VERSION 5.8 ;
BUSBITCHARS "[]" ;
DIVIDERCHAR "/" ;
UNITS
    DATABASE MICRONS 1000 ;
END UNITS

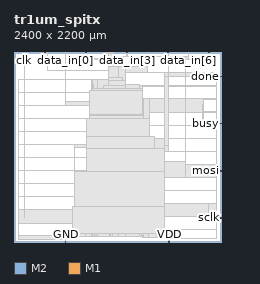
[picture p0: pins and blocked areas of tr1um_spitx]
MACRO tr1um_spitx
  FOREIGN tr1um_spitx 0 0 ;
  CLASS BLOCK ;
  SIZE 2400 BY 2200 ;
  PIN GND
    DIRECTION INOUT ;
    USE SIGNAL ;
    PORT
      LAYER M2 ;
        RECT  593.7 0 599.7 6 ;
    END
  END GND
  PIN VDD
    DIRECTION INOUT ;
    USE SIGNAL ;
    PORT
      LAYER M2 ;
        RECT  1792.5 0 1798.5 6 ;
    END
  END VDD
  PIN busy
    DIRECTION OUTPUT ;
    USE SIGNAL ;
    PORT
      LAYER M1 ;
        RECT  2396.4 1367.1 2400 1370.7 ;
    END
  END busy
  PIN clk
    DIRECTION INPUT ;
    USE SIGNAL ;
    PORT
      LAYER M2 ;
        RECT  118.5 2194 124.5 2200 ;
    END
  END clk
  PIN data_in[0]
    DIRECTION INPUT ;
    USE SIGNAL ;
    PORT
      LAYER M2 ;
        RECT  593.7 2194 599.7 2200 ;
    END
  END data_in[0]
  PIN data_in[1]
    DIRECTION INPUT ;
    USE SIGNAL ;
    PORT
      LAYER M2 ;
        RECT  831.3 2194 837.3 2200 ;
    END
  END data_in[1]
  PIN data_in[2]
    DIRECTION INPUT ;
    USE SIGNAL ;
    PORT
      LAYER M2 ;
        RECT  1068.9 2194 1074.9 2200 ;
    END
  END data_in[2]
  PIN data_in[3]
    DIRECTION INPUT ;
    USE SIGNAL ;
    PORT
      LAYER M2 ;
        RECT  1306.5 2194 1312.5 2200 ;
    END
  END data_in[3]
  PIN data_in[4]
    DIRECTION INPUT ;
    USE SIGNAL ;
    PORT
      LAYER M2 ;
        RECT  1544.1 2194 1550.1 2200 ;
    END
  END data_in[4]
  PIN data_in[5]
    DIRECTION INPUT ;
    USE SIGNAL ;
    PORT
      LAYER M2 ;
        RECT  1781.7 2194 1787.7 2200 ;
    END
  END data_in[5]
  PIN data_in[6]
    DIRECTION INPUT ;
    USE SIGNAL ;
    PORT
      LAYER M2 ;
        RECT  2019.3 2194 2025.3 2200 ;
    END
  END data_in[6]
  PIN data_in[7]
    DIRECTION INPUT ;
    USE SIGNAL ;
    PORT
      LAYER M2 ;
        RECT  2256.9 2194 2262.9 2200 ;
    END
  END data_in[7]
  PIN done
    DIRECTION OUTPUT ;
    USE SIGNAL ;
    PORT
      LAYER M1 ;
        RECT  2396.4 1912.5 2400 1916.1 ;
    END
  END done
  PIN mosi
    DIRECTION OUTPUT ;
    USE SIGNAL ;
    PORT
      LAYER M1 ;
        RECT  2396.4 821.7 2400 825.3 ;
    END
  END mosi
  PIN sclk
    DIRECTION OUTPUT ;
    USE SIGNAL ;
    PORT
      LAYER M1 ;
        RECT  2396.4 276.3 2400 279.9 ;
    END
  END sclk
  PIN start
    DIRECTION INPUT ;
    USE SIGNAL ;
    PORT
      LAYER M2 ;
        RECT  356.1 2194 362.1 2200 ;
    END
  END start
  OBS
    LAYER M1 ;
     RECT  53.1 29.1 54.9 1883.9 ;
     RECT  54.9 29.1 595 69.5 ;
     RECT  54.9 1579.7 595.8 1581.5 ;
     RECT  595 28.3 598.4 69.5 ;
     RECT  598.4 67.7 692.3 69.5 ;
     RECT  54.9 218.9 692.3 371.9 ;
     RECT  54.9 1126.1 703.8 1127.9 ;
     RECT  54.9 521.3 720 523.1 ;
     RECT  54.9 672.5 720 674.3 ;
     RECT  54.9 823.7 784.8 825.5 ;
     RECT  692.3 67.7 832.5 371.9 ;
     RECT  720 521.3 832.5 674.3 ;
     RECT  54.9 1428.5 844.2 1430.3 ;
     RECT  844.2 1422 865.8 1430.3 ;
     RECT  54.9 1277.3 871.2 1279.1 ;
     RECT  703.8 1098 873.8 1127.9 ;
     RECT  871.2 1260 873.8 1279.1 ;
     RECT  784.8 817.2 882 825.5 ;
     RECT  54.9 974.9 882 976.7 ;
     RECT  865.8 1416.6 887.5 1430.3 ;
     RECT  595.8 1579.7 887.5 1623.6 ;
     RECT  882 817.2 890.3 976.7 ;
     RECT  873.8 1098 890.3 1279.1 ;
     RECT  887.5 1416.6 890.3 1623.6 ;
     RECT  832.5 67.7 895.8 674.3 ;
     RECT  890.3 817.2 895.8 1623.6 ;
     RECT  54.9 1730.9 901.3 1732.7 ;
     RECT  54.9 1882.1 901.3 1883.9 ;
     RECT  895.8 67.7 904 1623.6 ;
     RECT  901.3 1730.9 904 1883.9 ;
     RECT  904 67.7 968.4 1883.9 ;
     RECT  833.4 2118.6 1092.6 2120.4 ;
     RECT  1092.6 2118.6 1103.4 2147.4 ;
     RECT  1103.4 2118.6 1116 2152.8 ;
     RECT  968.4 61.2 1135.5 1883.9 ;
     RECT  390.6 1983.6 1135.5 1985.4 ;
     RECT  1135.5 61.2 1211.4 1985.4 ;
     RECT  1211.4 61.2 1294.2 2028.6 ;
     RECT  1116 2145.6 1310.4 2152.8 ;
     RECT  1294.2 61.2 1456.2 1828.8 ;
     RECT  1456.2 61.2 1487.8 1807.7 ;
     RECT  1487.8 61.2 1492.2 1656.5 ;
     RECT  1492.2 55.8 1493.3 1656.5 ;
     RECT  1493.3 747.5 1498.8 1656.5 ;
     RECT  1493.3 55.8 1499.4 619.2 ;
     RECT  1294.2 1957.1 1548 2028.6 ;
     RECT  1499.4 55.8 1553.4 457.2 ;
     RECT  1553.4 55.8 1556.5 448.8 ;
     RECT  1498.8 1352.3 1564.2 1656.5 ;
     RECT  1499.4 596.3 1580.4 619.2 ;
     RECT  1498.8 1049.9 1623.6 1224 ;
     RECT  1556.5 55.8 1661.4 446.9 ;
     RECT  1661.4 61.2 1696.8 446.9 ;
     RECT  1548 1957.1 1740.6 1958.9 ;
     RECT  1623.6 1049.9 1785.6 1202.9 ;
     RECT  1696.8 61.2 1793.8 144.5 ;
     RECT  1793.8 43.3 1797.2 144.5 ;
     RECT  1310.4 2145.6 1983.6 2147.4 ;
     RECT  1498.8 747.5 1985.4 932.4 ;
     RECT  1983.6 2107.8 2023.2 2147.4 ;
     RECT  1564.2 1352.3 2188.8 1354.1 ;
     RECT  1564.2 1503.5 2190.6 1656.5 ;
     RECT  1696.8 293.9 2253.6 446.9 ;
     RECT  2023.2 2107.8 2260.8 2109.6 ;
     RECT  1797.2 44.1 2339.1 45.9 ;
     RECT  1797.2 142.7 2339.1 144.5 ;
     RECT  2253.6 277.2 2339.1 446.9 ;
     RECT  1580.4 596.3 2339.1 598.1 ;
     RECT  1985.4 747.5 2339.1 900.5 ;
     RECT  1785.6 1049.9 2339.1 1051.7 ;
     RECT  1785.6 1201.1 2339.1 1202.9 ;
     RECT  2188.8 1352.3 2339.1 1369.8 ;
     RECT  2190.6 1503.5 2339.1 1505.3 ;
     RECT  2190.6 1654.7 2339.1 1656.5 ;
     RECT  1487.8 1805.9 2339.1 1807.7 ;
     RECT  1740.6 1913.4 2339.1 1958.9 ;
     RECT  2339.1 44.1 2340.9 1958.9 ;
     RECT  2340.9 277.2 2398.2 279 ;
     RECT  2340.9 822.6 2398.2 824.4 ;
     RECT  2340.9 1368 2398.2 1369.8 ;
     RECT  2340.9 1913.4 2398.2 1915.2 ;
    LAYER M2 ;
     RECT  595.2 3 598.2 28.3 ;
     RECT  595 28.3 598.4 31.7 ;
     RECT  1794 3 1797 43.3 ;
     RECT  1793.8 43.3 1797.2 46.7 ;
     RECT  1659 55.2 1662 60.6 ;
     RECT  967.8 60.6 970.8 78.2 ;
     RECT  1491.6 55.2 1494.6 78.2 ;
     RECT  1659 60.6 1743 78.2 ;
     RECT  748.8 78.2 752.2 96.8 ;
     RECT  929.4 78.2 970.8 96.8 ;
     RECT  1110 78.2 1113.4 96.8 ;
     RECT  1290.6 78.2 1294 96.8 ;
     RECT  1471.2 78.2 1494.6 96.8 ;
     RECT  1651.8 78.2 1743 96.8 ;
     RECT  724.7 96.8 752.2 97 ;
     RECT  905.3 96.8 970.8 97 ;
     RECT  1085.9 96.8 1113.4 97 ;
     RECT  1266.5 96.8 1294 97 ;
     RECT  1085.9 97 1132.8 97.4 ;
     RECT  1447.1 96.8 1494.6 97.4 ;
     RECT  1627.7 96.8 1743 97.4 ;
     RECT  903 97 970.8 102.65 ;
     RECT  1081.2 97.4 1132.8 102.65 ;
     RECT  1264.8 97 1311 102.65 ;
     RECT  1443 97.4 1743 102.65 ;
     RECT  681.6 97 771 102.7 ;
     RECT  894.4 102.65 1132.8 102.7 ;
     RECT  1255.6 102.65 1311 102.7 ;
     RECT  1436.2 102.65 1743 102.7 ;
     RECT  2253 276.6 2347.8 279.6 ;
     RECT  2253 279.6 2256 366 ;
     RECT  681.6 102.7 1743 406.5 ;
     RECT  703.2 406.5 1743 819.6 ;
     RECT  2334 822 2347.8 825 ;
     RECT  843.6 819.6 1743 1078.8 ;
     RECT  703.2 819.6 706.2 1100.4 ;
     RECT  1740 1078.8 1743 1119 ;
     RECT  843.6 1078.8 1624.2 1224.6 ;
     RECT  2334 1367.4 2347.8 1370.4 ;
     RECT  843.6 1224.6 1564.8 1424.4 ;
     RECT  876 1424.4 1496.4 1466.9 ;
     RECT  876 1466.9 1490.9 1472.4 ;
     RECT  2188.2 1367.4 2191.2 1586.4 ;
     RECT  876 1472.4 1489.2 1759.1 ;
     RECT  913.8 1759.1 1489.2 1774.6 ;
     RECT  913.8 1774.6 1482.7 1774.8 ;
     RECT  913.8 1774.8 1294.8 1780.8 ;
     RECT  1037.4 1780.8 1294.8 1809.6 ;
     RECT  913.8 1780.8 916.8 1829.4 ;
     RECT  1453.8 1774.8 1456.8 1829.4 ;
     RECT  1092 1809.6 1294.8 1867.2 ;
     RECT  1092 1867.2 1257 1907.7 ;
     RECT  1740 1119 1786.2 1915.8 ;
     RECT  2334 1912.8 2347.8 1915.8 ;
     RECT  1092 1907.7 1213.8 2029.2 ;
     RECT  1983 930 1986 2110.2 ;
     RECT  390 1983 393 2188.2 ;
     RECT  1092 2029.2 1149 2188.2 ;
     RECT  120 282 123 2197 ;
     RECT  357.6 2188.2 393 2197 ;
     RECT  595.2 1621.2 598.2 2197 ;
     RECT  832.8 2118 835.8 2197 ;
     RECT  1070.4 2188.2 1149 2197 ;
     RECT  1308 2150.4 1311 2197 ;
     RECT  1545.6 2026.2 1548.6 2197 ;
     RECT  1783.2 1915.8 1786.2 2197 ;
     RECT  2020.8 2145 2023.8 2197 ;
     RECT  2258.4 2107.2 2261.4 2197 ;
     RECT  373.8 2197 393 2198.5 ;
     RECT  1086.6 2197 1149 2198.5 ;
  END
END tr1um_spitx
END LIBRARY
